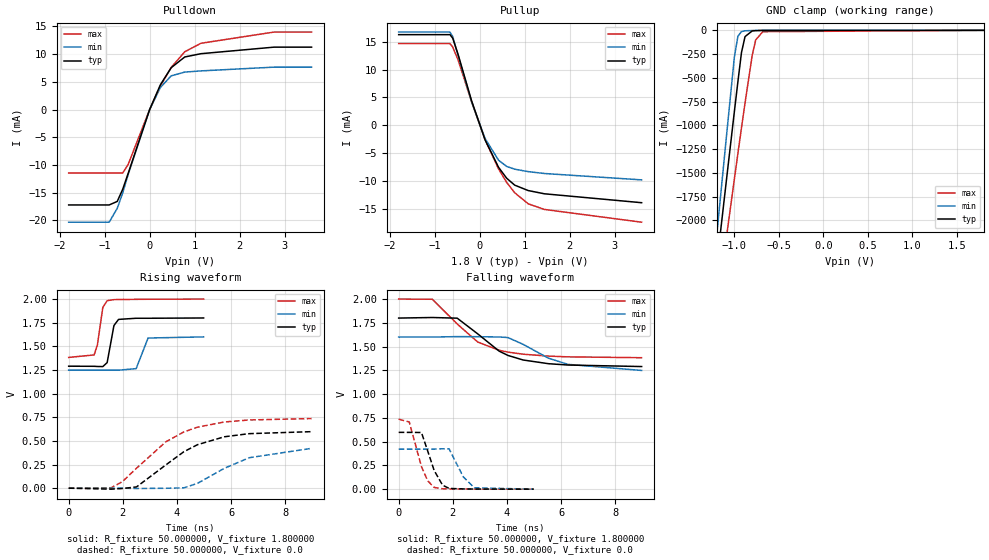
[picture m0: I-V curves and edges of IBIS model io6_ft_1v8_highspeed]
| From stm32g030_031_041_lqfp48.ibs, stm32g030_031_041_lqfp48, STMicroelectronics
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|   Model io6_ft_1v8_highspeed
[Model]  io6_ft_1v8_highspeed
Model_type I/O
Polarity   Non-Inverting
Enable   Active-Low
Vinl =   0.540000V
Vinh =   1.260000V
Vmeas =  0.900000V
Cref =   40.000000pF
Rref =   100.000000M
Vref =   0.0V
C_comp   1.277600pF   1.236700pF   1.315100pF
[Temperature Range]   25.000000   -40.000000   0.125000k
[Pullup Reference]   1.800000V   1.600000V   2.000000V
[Pulldown Reference]   0.0V   0.0V   0.0V
[POWER Clamp Reference]   1.800000V   1.600000V   2.000000V
[GND Clamp Reference]   0.0V   0.0V   0.0V
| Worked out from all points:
|   slope of the pulldown table from 0 to 0.27 V, typ, clamps not added: 54.7 ohm
|   slope of the pullup table from 0 to 0.27 V, typ, clamps not added: 50.6 ohm
|   GND clamp passes 1 mA (typ) near -0.66 V on its own axis
|   rising waveform, R_fixture 50.000000, V_fixture 1.800000: 20-80 % time 166ps typ, 169ps min, 180ps max; typ from 1.29 V to 1.8 V
|   rising waveform, R_fixture 50.000000, V_fixture 0.0: 20-80 % time 1.84ns typ, 1.87ns min, 1.92ns max; typ from 0 V to 0.598 V
|   falling waveform, R_fixture 50.000000, V_fixture 1.800000: 20-80 % time 1.52ns typ, 1.61ns min, 1.5ns max; typ from 1.8 V to 1.29 V
|   falling waveform, R_fixture 50.000000, V_fixture 0.0: 20-80 % time 439ps typ, 480ps min, 450ps max; typ from 0.598 V to 0 V
[Pulldown]
|Voltage   I(typ)   I(min)   I(max)
-1.8V     -17.22mA   -20.33mA   -11.45mA
-900mV    -17.22mA   -20.33mA   -11.45mA
-720mV    -16.58mA   -17.82mA   -11.45mA
-600mV    -14.41mA   -15.08mA   -11.45mA
-480mV    -11.58mA   -11.79mA   -9.954mA
0V        10fA       11fA       0A
240mV     4.49mA     3.999mA    4.291mA
480mV     7.563mA    6.085mA    7.612mA
780mV     9.487mA    6.76mA     10.43mA
1.14V     10.08mA    6.976mA    11.96mA
2.76V     11.26mA    7.652mA    13.98mA
3.6V      11.26mA    7.652mA    13.98mA
[Pullup]
|Voltage   I(typ)   I(min)   I(max)
-1.8V     16.28mA    16.74mA    14.68mA
-660mV    16.28mA    16.74mA    14.68mA
-600mV    15.66mA    15.96mA    14.07mA
-480mV    12.75mA    12.58mA    11.77mA
-180mV    4.421mA    4.232mA    4.226mA
120mV     -2.605mA   -2.366mA   -2.563mA
420mV     -7.546mA   -6.273mA   -7.834mA
600mV     -9.499mA   -7.385mA   -10.25mA
780mV     -10.75mA   -7.883mA   -12.12mA
1.08V     -11.72mA   -8.32mA    -14.1mA
1.44V     -12.3mA    -8.657mA   -15.11mA
3.6V      -13.9mA    -9.8mA     -17.4mA
[GND_clamp]
|Voltage   I(typ)   I(min)   I(max)
-1.8V     -7.471A    -7.973A    -7.298A
-1.2V     -2.489A    -2.18A     -2.954A
-1.16V    -2.16A     -1.797A    -2.674A
-1.08V    -1.505A    -1.034A    -2.118A
-1V       -857.9mA   -283.1mA   -1.568A
-960mV    -540.4mA   -62.14mA   -1.296A
-920mV    -234.4mA   -13.75mA   -1.028A
-880mV    -66.29mA   -4.855mA   -765.3mA
-800mV    -6.505mA   -2.056mA   -266mA
-760mV    -3.074mA   -1.45mA    -100.4mA
-680mV    -1.215mA   -557.1uA   -14.19mA
1.8V      0A         0A         0A
[POWER_clamp]
|Voltage   I(typ)   I(min)   I(max)
-1.8V     0A         0A         0A
0V        0A         0A         0A
[Ramp]
| variable   typ   min   max
dV/dt_r  0.34918/1.74945n   0.253/1.41472n   0.43502/1.86944n
dV/dt_f  0.30018/1.46014n   0.211/1.35727n   0.36678/1.46795n
R_load = 50.000000
[Rising Waveform]
R_fixture= 50.000000
V_fixture= 1.800000
V_fixture_min= 1.600000
V_fixture_max= 2.000000
|time   V(typ)   V(min)   V(max)
0s        1.29V      1.249V     1.383V
940.9ps   1.289V     1.249V     1.409V
1.061ns   1.287V     1.249V     1.515V
1.261ns   1.286V     1.249V     1.911V
1.421ns   1.328V     1.249V     1.983V
1.672ns   1.72V      1.249V     1.994V
1.842ns   1.785V     1.248V     1.995V
2.492ns   1.797V     1.264V     1.997V
2.933ns   1.797V     1.588V     1.998V
4.985ns   1.8V       1.6V       2V
[Rising Waveform]
R_fixture= 50.000000
V_fixture= 0.0
V_fixture_min= 0.0
V_fixture_max= 0.0
|time   V(typ)   V(min)   V(max)
0s        524.8nV    1.223uV    -3.017uV
1.568ns   -10.41mV   -6.065uV   4.673mV
1.982ns   -3.472mV   140.5uV    68.49mV
2.505ns   13.21mV    -3.419mV   210.9mV
3.586ns   245.3mV    -1.024mV   489.7mV
4.252ns   385.3mV    3.462mV    594.6mV
4.757ns   459.9mV    50.71mV    645.5mV
5.748ns   543.6mV    209.9mV    699.9mV
6.667ns   576.6mV    322mV      721.5mV
8.973ns   597.8mV    421.4mV    736.3mV
[Falling Waveform]
R_fixture= 50.000000
V_fixture= 1.800000
V_fixture_min= 1.600000
V_fixture_max= 2.000000
|time   V(typ)   V(min)   V(max)
0s        1.8V       1.6V       2V
1.243ns   1.806V     1.6V       1.998V
2.162ns   1.799V     1.605V     1.738V
2.919ns   1.634V     1.604V     1.548V
3.712ns   1.452V     1.601V     1.461V
4.036ns   1.407V     1.595V     1.442V
4.595ns   1.359V     1.524V     1.42V
5.532ns   1.32V      1.378V     1.4V
6.252ns   1.306V     1.313V     1.392V
8.973ns   1.29V      1.249V     1.383V
[Falling Waveform]
R_fixture= 50.000000
V_fixture= 0.0
V_fixture_min= 0.0
V_fixture_max= 0.0
|time   V(typ)   V(min)   V(max)
0s        597.8mV    421.4mV    736.3mV
390.4ps   597.3mV    421.5mV    707.1mV
840.8ps   596.3mV    421.6mV    238.2mV
1.071ns   402.6mV    421.5mV    88.29mV
1.311ns   196.4mV    421mV      18.32mV
1.622ns   41.91mV    424.9mV    4.034mV
1.862ns   7.912mV    424.7mV    2.507mV
2.382ns   2.543mV    130.8mV    1.293mV
2.793ns   1.353mV    14.28mV    859.5uV
4.985ns   524.8nV    1.223uV    -3.017uV
